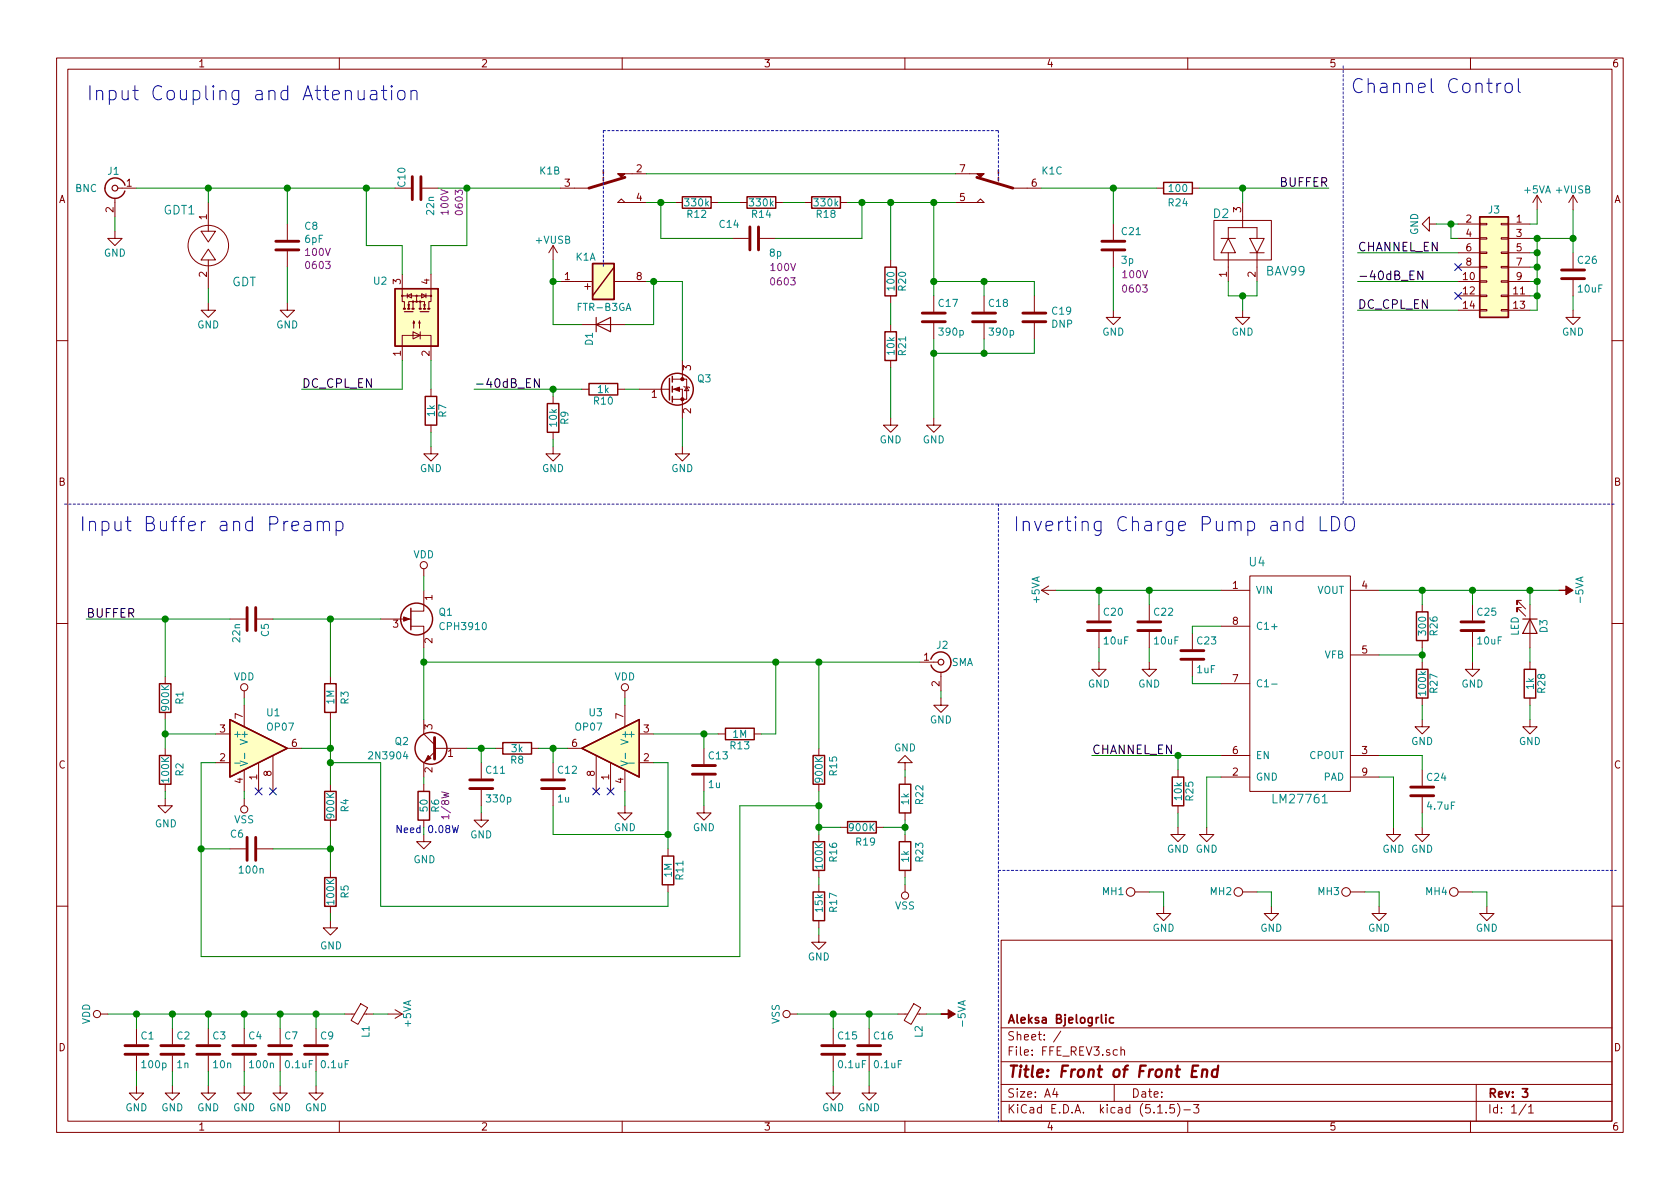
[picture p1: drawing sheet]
<svg xmlns="http://www.w3.org/2000/svg" width="297mm" height="210mm" viewBox="0 0 297 210" stroke-linecap="round" stroke-linejoin="round" font-family="sans-serif">
<defs><g id="words">
<g font-size="3.5" fill="#0000c2">
<text x="15.2" y="17.8">Input Coupling and Attenuation</text>
<text x="238.8" y="16.5">Channel Control</text>
<text x="14" y="94">Input Buffer and Preamp</text>
<text x="179.1" y="94">Inverting Charge Pump and LDO</text>
</g>
<text font-size="2.8" fill="#840000" x="178" y="190.5">Title: Front of Front End</text>
<g font-size="2.1">
<text x="226.3" y="33">BUFFER</text>
<text x="240" y="44.4">CHANNEL_EN</text>
<text x="240" y="49.5">-40dB_EN</text>
<text x="240" y="54.6">DC_CPL_EN</text>
<text x="53.3" y="68.6">DC_CPL_EN</text>
<text x="83.8" y="68.6">-40dB_EN</text>
<text x="15.2" y="109.2">BUFFER</text>
<text x="193" y="133.3">CHANNEL_EN</text>
</g>
<g font-size="2.1" fill="#008484">
<text x="28.9" y="37.9">GDT1</text>
<text x="214.6" y="38.6">D2</text>
<text x="40.9" y="50.6">GDT</text>
<text x="223.9" y="48.7">BAV99</text>
<text x="220.9" y="100.1">U4</text>
<text x="225.4" y="142.1">LM27761</text>
</g>
<g font-size="2.1" fill="#840000">
<text x="178" y="184">Sheet: /</text>
<text x="178" y="181">Aleksa Bjelogrlic</text>
<text x="178" y="186.7">File: FFE_REV3.sch</text>
<text x="178" y="196.9">KiCad E.D.A. kicad (5.1.5)-3</text>
<text x="178" y="194.1">Size: A4</text>
<text x="200" y="194.1">Date:</text>
<text x="263" y="194.1">Rev: 3</text>
<text x="263" y="196.9">Id: 1/1</text>
</g>
<g font-size="1.8" fill="#840000">
<text x="35" y="11.9">1</text>
<text x="85" y="11.9">2</text>
<text x="135" y="11.9">3</text>
<text x="185" y="11.9">4</text>
<text x="235" y="11.9">5</text>
<text x="285" y="11.9">6</text>
<text x="10.4" y="35.9">A</text>
<text x="22.4" y="33">1</text>
<text x="99.8" y="33">3</text>
<text x="112.5" y="30.5">2</text>
<text x="112.5" y="35.6">4</text>
<text x="169.7" y="35.6">5</text>
<text x="169.7" y="30.5">7</text>
<text x="182.4" y="33">6</text>
<text x="285.4" y="35.9">A</text>
<text x="20.1" y="37.6" transform="rotate(-90 20.1 37.6)">2</text>
<text x="36.6" y="38.8" transform="rotate(-90 36.6 38.8)">1</text>
<text x="219.5" y="37.6" transform="rotate(-90 219.5 37.6)">3</text>
<text x="259.2" y="39.4">2</text>
<text x="259.2" y="41.9">4</text>
<text x="268.1" y="39.4">1</text>
<text x="268.1" y="41.9">3</text>
<text x="259.2" y="44.4">6</text>
<text x="259.2" y="47">8</text>
<text x="268.1" y="44.4">5</text>
<text x="268.1" y="47">7</text>
<text x="36.6" y="49" transform="rotate(-90 36.6 49)">2</text>
<text x="70.9" y="50.3" transform="rotate(-90 70.9 50.3)">3</text>
<text x="75.9" y="50.3" transform="rotate(-90 75.9 50.3)">4</text>
<text x="99.8" y="49.5">1</text>
<text x="112.5" y="49.5">8</text>
<text x="216.9" y="49" transform="rotate(-90 216.9 49)">1</text>
<text x="222" y="49" transform="rotate(-90 222 49)">2</text>
<text x="258.7" y="49.5">10</text>
<text x="258.7" y="52.1">12</text>
<text x="267.6" y="52.1">11</text>
<text x="268.1" y="49.5">9</text>
<text x="258.7" y="54.6">14</text>
<text x="267.6" y="54.6">13</text>
<text x="70.9" y="63" transform="rotate(-90 70.9 63)">1</text>
<text x="75.9" y="63" transform="rotate(-90 75.9 63)">2</text>
<text x="122.2" y="65.5" transform="rotate(-90 122.2 65.5)">3</text>
<text x="115.2" y="70.4">1</text>
<text x="122.2" y="73.1" transform="rotate(-90 122.2 73.1)">2</text>
<text x="10.4" y="85.9">B</text>
<text x="285.4" y="85.9">B</text>
<text x="76.5" y="106.1" transform="rotate(-90 76.5 106.1)">1</text>
<text x="218" y="104.1">1</text>
<text x="240.8" y="104.1">4</text>
<text x="69.5" y="111">3</text>
<text x="76.5" y="113.8" transform="rotate(-90 76.5 113.8)">2</text>
<text x="218" y="110.5">8</text>
<text x="163.3" y="116.8">1</text>
<text x="240.8" y="115.6">5</text>
<text x="166.1" y="121.4" transform="rotate(-90 166.1 121.4)">2</text>
<text x="218" y="120.6">7</text>
<text x="38.9" y="129.5">3</text>
<text x="42.9" y="127.1" transform="rotate(-90 42.9 127.1)">7</text>
<text x="76.5" y="129" transform="rotate(-90 76.5 129)">3</text>
<text x="110.2" y="127.1" transform="rotate(-90 110.2 127.1)">7</text>
<text x="113.8" y="129.5">3</text>
<text x="10.4" y="135.9">C</text>
<text x="38.9" y="134.6">2</text>
<text x="45.5" y="137.9" transform="rotate(-90 45.5 137.9)">1</text>
<text x="48" y="137.3" transform="rotate(-90 48 137.3)">8</text>
<text x="51.6" y="132.1">6</text>
<text x="76.5" y="136.6" transform="rotate(-90 76.5 136.6)">2</text>
<text x="79.2" y="133.9">1</text>
<text x="101.1" y="132.1">6</text>
<text x="105.2" y="137.3" transform="rotate(-90 105.2 137.3)">8</text>
<text x="107.7" y="137.9" transform="rotate(-90 107.7 137.9)">1</text>
<text x="113.8" y="134.6">2</text>
<text x="218" y="137.2">2</text>
<text x="218" y="133.3">6</text>
<text x="240.8" y="133.3">3</text>
<text x="240.8" y="137.2">9</text>
<text x="285.4" y="135.9">C</text>
<text x="42.9" y="138.5" transform="rotate(-90 42.9 138.5)">4</text>
<text x="110.2" y="138.5" transform="rotate(-90 110.2 138.5)">4</text>
<text x="10.4" y="185.9">D</text>
<text x="285.4" y="185.9">D</text>
<text x="35" y="199.9">1</text>
<text x="85" y="199.9">2</text>
<text x="135" y="199.9">3</text>
<text x="185" y="199.9">4</text>
<text x="235" y="199.9">5</text>
<text x="285" y="199.9">6</text>
</g>
<g font-size="1.8" fill="#008484">
<text x="13.3" y="34">BNC</text>
<text x="19.1" y="30.9">J1</text>
<text x="71.7" y="33" transform="rotate(-90 71.7 33)">C10</text>
<text x="95.5" y="30.9">K1B</text>
<text x="184.3" y="30.9">K1C</text>
<text x="206.8" y="34">100</text>
<text x="269.5" y="34.2">+5VA +VUSB</text>
<text x="53.9" y="40.6">C8</text>
<text x="76.8" y="37.9" transform="rotate(-90 76.8 37.9)">22n</text>
<text x="121.2" y="36.5">330k</text>
<text x="121.6" y="38.5">R12</text>
<text x="127.3" y="40.3">C14</text>
<text x="132.7" y="36.5">330k</text>
<text x="133" y="38.5">R14</text>
<text x="144.1" y="36.5">330k</text>
<text x="144.4" y="38.5">R18</text>
<text x="198.4" y="41.6">C21</text>
<text x="206.7" y="36.5">R24</text>
<text x="250.7" y="41.6" transform="rotate(-90 250.7 41.6)">GND</text>
<text x="263.2" y="37.8">J3</text>
<text x="18.4" y="45.4">GND</text>
<text x="53.9" y="42.9">6pF</text>
<text x="94.8" y="43.1">+VUSB</text>
<text x="101.8" y="46.1">K1A</text>
<text x="136.1" y="45.4">8p</text>
<text x="198.3" y="46.7">3p</text>
<text x="279" y="46.7">C26</text>
<text x="66.1" y="50.3">U2</text>
<text x="158.2" y="51.2" transform="rotate(-90 158.2 51.2)">100</text>
<text x="160.2" y="51.4" transform="rotate(-90 160.2 51.4)">R20</text>
<text x="279.1" y="51.7">10uF</text>
<text x="34.9" y="58.1">GND</text>
<text x="48.8" y="58.1">GND</text>
<text x="102.3" y="55">FTR-B3GA</text>
<text x="166" y="54.3">C17</text>
<text x="166.2" y="59.4">390p</text>
<text x="174.9" y="54.3">C18</text>
<text x="175.1" y="59.4">390p</text>
<text x="186" y="58">DNP</text>
<text x="186.1" y="55.6">C19</text>
<text x="194.9" y="59.4">GND</text>
<text x="217.8" y="59.4">GND</text>
<text x="276.2" y="59.4">GND</text>
<text x="104.8" y="61.1" transform="rotate(-90 104.8 61.1)">D1</text>
<text x="158.2" y="62.7" transform="rotate(-90 158.2 62.7)">10k</text>
<text x="160.2" y="62.8" transform="rotate(-90 160.2 62.8)">R21</text>
<text x="105.1" y="71.5">R10</text>
<text x="105.7" y="69.5">1k</text>
<text x="123.4" y="67.6">Q3</text>
<text x="76.9" y="73.6" transform="rotate(-90 76.9 73.6)">1k</text>
<text x="78.9" y="73.8" transform="rotate(-90 78.9 73.8)">R7</text>
<text x="98.5" y="75.4" transform="rotate(-90 98.5 75.4)">10k</text>
<text x="100.5" y="75" transform="rotate(-90 100.5 75)">R9</text>
<text x="74.2" y="83.5">GND</text>
<text x="95.8" y="83.5">GND</text>
<text x="118.7" y="83.5">GND</text>
<text x="155.5" y="78.4">GND</text>
<text x="163.1" y="78.4">GND</text>
<text x="73.1" y="98.7">VDD</text>
<text x="183.8" y="106.6" transform="rotate(-90 183.8 106.6)">+5VA</text>
<text x="222" y="105">VIN</text>
<text x="232.8" y="105">VOUT</text>
<text x="280" y="106.4" transform="rotate(-90 280 106.4)">-5VA</text>
<text x="42.5" y="113.5" transform="rotate(-90 42.5 113.5)">22n</text>
<text x="47.5" y="112.5" transform="rotate(-90 47.5 112.5)">C5</text>
<text x="77.6" y="108.9">Q1</text>
<text x="78.1" y="111.4">CPH3910</text>
<text x="195.2" y="108.9">C20</text>
<text x="195.3" y="114">10uF</text>
<text x="204.1" y="108.9">C22</text>
<text x="204.2" y="114">10uF</text>
<text x="211.7" y="114">C23</text>
<text x="222" y="111.4">C1+</text>
<text x="252.1" y="112.2" transform="rotate(-90 252.1 112.2)">300</text>
<text x="254.2" y="112.3" transform="rotate(-90 254.2 112.3)">R26</text>
<text x="261.3" y="108.9">C25</text>
<text x="261.3" y="114">10uF</text>
<text x="268.5" y="112.5" transform="rotate(-90 268.5 112.5)">LED</text>
<text x="273.6" y="111.9" transform="rotate(-90 273.6 111.9)">D3</text>
<text x="165.7" y="114.7">J2</text>
<text x="168.2" y="117.8">SMA</text>
<text x="211.7" y="119">1uF</text>
<text x="234.2" y="116.5">VFB</text>
<text x="29.9" y="125.5" transform="rotate(-90 29.9 125.5)">900K</text>
<text x="32.4" y="124.5" transform="rotate(-90 32.4 124.5)">R1</text>
<text x="41.3" y="120.3">VDD</text>
<text x="59.1" y="124.5" transform="rotate(-90 59.1 124.5)">1M</text>
<text x="61.6" y="124.5" transform="rotate(-90 61.6 124.5)">R3</text>
<text x="108.6" y="120.3">VDD</text>
<text x="192.4" y="121.6">GND</text>
<text x="201.2" y="121.6">GND</text>
<text x="222" y="121.5">C1-</text>
<text x="252.1" y="122.8" transform="rotate(-90 252.1 122.8)">100k</text>
<text x="254.2" y="122.5" transform="rotate(-90 254.2 122.5)">R27</text>
<text x="258.4" y="121.6">GND</text>
<text x="271.2" y="121.9" transform="rotate(-90 271.2 121.9)">1k</text>
<text x="273.2" y="122.5" transform="rotate(-90 273.2 122.5)">R28</text>
<text x="41.1" y="130.4">+</text>
<text x="43.8" y="131.2" transform="rotate(-90 43.8 131.2)">V+</text>
<text x="47.2" y="126.7">U1</text>
<text x="47.3" y="129.2">OP07</text>
<text x="69.9" y="131.7">Q2</text>
<text x="101.8" y="129.2">OP07</text>
<text x="104.2" y="126.7">U3</text>
<text x="111.1" y="131.2" transform="rotate(-90 111.1 131.2)">V+</text>
<text x="111.5" y="130.4">+</text>
<text x="129.6" y="130.5">1M</text>
<text x="164.4" y="127.9">GND</text>
<text x="249.5" y="131.7">GND</text>
<text x="268.6" y="131.7">GND</text>
<text x="32.4" y="137.2" transform="rotate(-90 32.4 137.2)">R2</text>
<text x="65.5" y="134.3">2N3904</text>
<text x="86" y="136.8">C11</text>
<text x="90.3" y="135">R8</text>
<text x="90.5" y="133">3k</text>
<text x="98.7" y="136.8">C12</text>
<text x="125.4" y="134.3">C13</text>
<text x="129.2" y="132.5">R13</text>
<text x="148" y="137.1" transform="rotate(-90 148 137.1)">R15</text>
<text x="158.1" y="132.9">GND</text>
<text x="222" y="134.2">EN</text>
<text x="231.5" y="134.2">CPOUT</text>
<text x="29.9" y="138.2" transform="rotate(-90 29.9 138.2)">100K</text>
<text x="61.6" y="143.6" transform="rotate(-90 61.6 143.6)">R4</text>
<text x="75.6" y="143.4" transform="rotate(-90 75.6 143.4)">50</text>
<text x="77.6" y="143.6" transform="rotate(-90 77.6 143.6)">R6</text>
<text x="86.2" y="141.9">330p</text>
<text x="98.7" y="141.9">1u</text>
<text x="125.3" y="139.4">1u</text>
<text x="145.5" y="138.2" transform="rotate(-90 145.5 138.2)">900K</text>
<text x="160.7" y="142.3" transform="rotate(-90 160.7 142.3)">1k</text>
<text x="163.2" y="142.2" transform="rotate(-90 163.2 142.2)">R22</text>
<text x="209" y="141.4" transform="rotate(-90 209 141.4)">10k</text>
<text x="211" y="141.5" transform="rotate(-90 211 141.5)">R25</text>
<text x="222" y="138">GND</text>
<text x="234" y="138">PAD</text>
<text x="252.4" y="138.1">C24</text>
<text x="252.5" y="143.2">4.7uF</text>
<text x="27.4" y="146.3">GND</text>
<text x="40.8" y="148.1">C6</text>
<text x="41.4" y="145.6">VSS</text>
<text x="59.1" y="144.6" transform="rotate(-90 59.1 144.6)">900K</text>
<text x="83.1" y="148.3">GND</text>
<text x="108.5" y="147">GND</text>
<text x="122.5" y="147">GND</text>
<text x="150.3" y="147">900K</text>
<text x="151.4" y="149.5">R19</text>
<text x="42.4" y="154.5">100n</text>
<text x="73.1" y="152.6">GND</text>
<text x="118.8" y="155.1" transform="rotate(-90 118.8 155.1)">1M</text>
<text x="120.8" y="155.5" transform="rotate(-90 120.8 155.5)">R11</text>
<text x="145.5" y="153.5" transform="rotate(-90 145.5 153.5)">100K</text>
<text x="148" y="152.3" transform="rotate(-90 148 152.3)">R16</text>
<text x="160.7" y="152.4" transform="rotate(-90 160.7 152.4)">1k</text>
<text x="163.2" y="152.3" transform="rotate(-90 163.2 152.3)">R23</text>
<text x="206.3" y="150.8">GND GND</text>
<text x="244.4" y="150.8">GND GND</text>
<text x="59.1" y="159.8" transform="rotate(-90 59.1 159.8)">100K</text>
<text x="61.6" y="158.8" transform="rotate(-90 61.6 158.8)">R5</text>
<text x="145.5" y="161.2" transform="rotate(-90 145.5 161.2)">15k</text>
<text x="148" y="161.2" transform="rotate(-90 148 161.2)">R17</text>
<text x="158.3" y="160.8">VSS</text>
<text x="195" y="158.3">MH1</text>
<text x="214" y="158.3">MH2</text>
<text x="233.1" y="158.3">MH3</text>
<text x="252.1" y="158.3">MH4</text>
<text x="56.6" y="167.9">GND</text>
<text x="203.8" y="164.8">GND</text>
<text x="222.8" y="164.8">GND</text>
<text x="241.9" y="164.8">GND</text>
<text x="260.9" y="164.8">GND</text>
<text x="142.8" y="169.8">GND</text>
<text x="15.9" y="181.1" transform="rotate(-90 15.9 181.1)">VDD</text>
<text x="25" y="183.8">C1</text>
<text x="31.3" y="183.8">C2</text>
<text x="37.7" y="183.8">C3</text>
<text x="44" y="183.8">C4</text>
<text x="50.4" y="183.8">C7</text>
<text x="56.7" y="183.8">C9</text>
<text x="65.3" y="183.4" transform="rotate(-90 65.3 183.4)">L1</text>
<text x="72.7" y="181.6" transform="rotate(-90 72.7 181.6)">+5VA</text>
<text x="137.8" y="181.1" transform="rotate(-90 137.8 181.1)">VSS</text>
<text x="148.2" y="183.8">C15</text>
<text x="154.6" y="183.8">C16</text>
<text x="163.1" y="183.4" transform="rotate(-90 163.1 183.4)">L2</text>
<text x="170.7" y="181.3" transform="rotate(-90 170.7 181.3)">-5VA</text>
<text x="25.2" y="188.9">100p</text>
<text x="31.3" y="188.9">1n</text>
<text x="37.8" y="188.9">10n</text>
<text x="44.3" y="188.9">100n</text>
<text x="50.5" y="188.9">0.1uF</text>
<text x="56.9" y="188.9">0.1uF</text>
<text x="148.3" y="188.9">0.1uF</text>
<text x="154.7" y="188.9">0.1uF</text>
<text x="22.2" y="196.5">GND</text>
<text x="28.5" y="196.5">GND</text>
<text x="34.9" y="196.5">GND</text>
<text x="41.2" y="196.5">GND</text>
<text x="47.6" y="196.5">GND</text>
<text x="53.9" y="196.5">GND</text>
<text x="145.4" y="196.5">GND</text>
<text x="151.7" y="196.5">GND</text>
</g>
<g font-size="1.8" fill="#840084">
<text x="79.3" y="37.9" transform="rotate(-90 79.3 37.9)">100V</text>
<text x="81.8" y="37.8" transform="rotate(-90 81.8 37.8)">0603</text>
<text x="54.1" y="45.3">100V</text>
<text x="54.3" y="47.6">0603</text>
<text x="136.4" y="47.9">100V</text>
<text x="136.5" y="50.5">0603</text>
<text x="198.6" y="49.2">100V</text>
<text x="198.7" y="51.7">0603</text>
<text x="79.4" y="144.5" transform="rotate(-90 79.4 144.5)">1/8W</text>
</g>
<text font-size="1.8" fill="#0000c2" x="69.8" y="147.3">Need 0.08W</text>
</g></defs>
<g fill="none" stroke="#840000" stroke-width=".18">
<path d="M10 10.3h277v189.9h-277zM12 12.2h273v186.1h-273zM60 10.3v1.9M110 10.3v1.9M160 10.3v1.9M210 10.3v1.9M260 10.3v1.9M20.3 35v3.3M20.8 33.3h3.3M36.8 35.8v5.1M50.8 39.6v2.8M69.8 33.3h2.8"/>
<path d="M74.7 33.3h2.8M99.1 33.3h5M109.2 30.7h5.1M110.5 35.8l-.6-.6-.7 .6h5.1M119.4 35.8h1.2M125.7 35.8h1.3M130.8 35.8h1.3M137.2 35.8h1.2M142.2 35.8h1.3M148.6 35.8h1.3M168.9 35.8h5.1l-.6-.6-.7 .6M168.9 30.7h5.1"/>
<path d="M179.1 33.3h5M196.8 39.6v2.8M204.5 33.3h1.2M210.8 33.3h1.3M214.6 39h10.2v7h-10.2zM219.7 35.8v4.5M252.7 39.6v-1.3l-1.2 1.3 1.2 1.3v-1.3h1.3M257.8 39.6h3.8M261.6 39.5h1.3v.2h-1.3zM265.4 39.5h1.3v.2h-1.3zM266.7 39.6h3.8M271.8 34.5l-.8 1.3"/>
<path d="M271.8 34.5v2.6M271.8 34.5l.7 1.3M278.1 34.5v2.6M278.1 34.5l-.7 1.3M278.1 34.5l.8 1.3M20.3 40.9v1.3h1.3l-1.3 1.2-1.3-1.2h1.3M35.6 40.9h2.5l-1.3 1.9zM36.8 53.6v1.3h1.3l-1.3 1.2-1.2-1.2h1.2M36.8 44.1l1.3 1.9h-2.5zM36.8 46v5M50.8 53.6v1.3h1.3l-1.3 1.2-1.3-1.2h1.3M50.8 44.4v2.8"/>
<path d="M71.1 48.5v4.8h.4v1.2M71.1 52.3h5.1M72 52.3l.8-.4v.8zM72 51.9v.8M72.1 53.8h.3l-.1 .6zM73 53.3h-.7v1.2M73 58.7l1.3 .6-1.3 .6zM73 54.5v-1.2h1.3v1.2M73.2 56.8l-.2 .3h.3l-.1-.3v1.2M73.7 52.3v1M74.2 56.8l-.2 .3h.3l-.1-.3v1.2M74.3 59.3h-3.2v4.4"/>
<path d="M74.3 59.3h1.9v4.4M74.3 53.3h.8v1.2M74.3 58.7v1.2M74.5 51.9l.8 .4-.8 .4zM74.9 53.8h.3l-.1 .6zM75.3 51.9v.8M76.2 48.5v4.8h-.4v1.2M97.8 43.4l.8 1.3M97.8 43.4v2.6M97.8 43.4l-.8 1.3M99.1 49.8h5.7M102.9 57.4h7.6"/>
<path d="M103.4 50.7h1M103.9 50.2v1M108.6 49.8h5.7M129.5 42.2h2.8M134.4 42.2h2.8M157.5 46v1.2M157.5 52.3v1.3M157.5 57.4v1.3M165.1 52.3v2.8M165.1 57.1v2.8M174 52.3v2.8M174 57.1v2.8"/>
<path d="M182.9 52.3v2.8M182.9 57.1v2.8M196.8 54.9v1.2h1.3l-1.3 1.3-1.2-1.3h1.2M196.8 44.4v2.8M215.9 42.2h2.5M217.2 40.3v1.9zM217.2 40.3h5zM217.2 42.2l1.2 2.5h-2.5zM217.2 44.7v5.1M219.7 54.9v1.2h1.3l-1.3 1.3-1.3-1.3h1.3M221 42.2h2.5l-1.3 2.5zM221 44.7h2.5"/>
<path d="M222.2 40.3v1.9zM222.2 44.7v5.1M257.8 52.3h3.8M257.8 42.2h3.8M257.8 49.8h3.8M257.8 44.7h3.8M257.8 54.9h3.8M257.8 47.2h3.8M261.6 54.7h1.3v.3h-1.3zM261.6 52.2h1.3v.2h-1.3zM261.6 49.7h1.3v.2h-1.3zM261.6 47.1h1.3v.3h-1.3z"/>
<path d="M261.6 44.6h1.3v.2h-1.3zM261.6 42h1.3v.3h-1.3zM265.4 54.7h1.3v.3h-1.3zM265.4 52.2h1.3v.2h-1.3zM265.4 49.7h1.3v.2h-1.3zM265.4 47.1h1.3v.3h-1.3zM265.4 44.6h1.3v.2h-1.3zM265.4 42h1.3v.3h-1.3zM266.7 52.3h3.8M266.7 42.2h3.8M266.7 49.8h3.8M266.7 44.7h3.8"/>
<path d="M266.7 54.9h3.8M266.7 47.2h3.8M278.1 54.9v1.2h1.3l-1.3 1.3-1.2-1.3h1.2M278.1 44.7v2.8M278.1 49.5v2.8M10 60.2h2M76.2 79v1.3h1.3l-1.3 1.2-1.3-1.2h1.3M76.2 68.8v1.3M76.2 75.2v1.2M97.8 79v1.3h1.3l-1.3 1.2-1.3-1.2h1.3M97.8 70.1v1.3M97.8 76.4v1.3"/>
<path d="M102.9 68.8h1.2M109.2 68.8h1.3M113 68.8h5.4M118.9 68.8h1.7v5.1M118.9 67.1h1.7M120.6 79v1.3h1.3l-1.3 1.2-1.2-1.2h1.2M120.6 67.1h.8v3.5h-2.5M120.6 63.7v3.4M120.9 68.3l.1 .1h.8l.1 .2M121.4 68.4l.4 .7h-.8zM157.5 73.9v1.3h1.2l-1.2 1.2-1.3-1.2h1.3M157.5 63.7v1.3"/>
<path d="M165.1 73.9v1.3h1.3l-1.3 1.2-1.3-1.2h1.3M285 60.2h2M10 110.3h2M29.2 119.6v1.3M40.6 109.5h2.8M45.5 109.5h2.8M58.4 119.6v1.3M67.3 109.5h5.3M72.6 110.7h2.3v3.8M74.9 104.4v3.7h-2.3M74.9 100.6v1.2M162.6 117.1h3.3"/>
<path d="M166.4 118.9v3.3M184.1 104.4l1.3 .8M184.1 104.4h2.6M185.4 103.6l-1.3 .8M194.3 117.1v1.3h1.3l-1.3 1.2-1.3-1.2h1.3M194.3 106.9v2.8M194.3 111.8v2.7M203.2 117.1v1.3h1.3l-1.3 1.2-1.3-1.2h1.3M203.2 106.9v2.8M203.2 111.8v2.7M210.8 112v2.8M210.8 116.8v2.8"/>
<path d="M215.9 104.4h5.1M215.9 110.7h5.1M221 101.8h17.8v38.1h-17.8zM238.8 104.4h5M238.8 115.8h5M251.5 106.9v1.3M251.5 113.3v1.2M251.5 117.1v1.3M260.3 117.1v1.3h1.3l-1.3 1.2-1.2-1.2h1.2M260.3 106.9v2.8M260.3 111.8v2.7M269 106.2h-.8v.7v-.7l1.5 1.5"/>
<path d="M269 107.4h-.8v.8v-.8l1.5 1.6M270.5 106.9v7.6M270.5 117.1v1.3M285 110.3h2M29.2 126v1.2M29.2 132.3v1.3M29.2 138.7v1.2M38.1 129.8h2.5M38.1 134.9h2.5M43.2 122.2v1.2M43.2 124.7v3.8M43.2 136.1v3.8"/>
<path d="M45.7 134.9v5M48.3 133.6v6.3M50.8 132.3h2.5M58.4 126v1.2M58.4 138.7v1.2M74.9 127.2v2.6l1.9 1.9M74.9 138.7v1.2M76.8 133l-1.9 1.9v2.5M76.8 132.3h5.7M85.1 134.9v2.8M85.1 139.7v2.8M87.6 132.3h1.3"/>
<path d="M94 132.3h1.2M97.8 134.9v2.8M97.8 139.7v2.8M100.3 132.3h2.6M105.4 133.6v6.3M107.9 134.9v5M110.5 122.2v1.2M110.5 124.7v3.8M110.5 136.1v3.8M113 129.8h2.6M113 134.9h2.6M124.5 132.3v2.8"/>
<path d="M124.5 137.2v2.7M127 129.8h1.3M133.3 129.8h1.3M144.8 132.3v1.3M144.8 138.7v1.2M160 134.9h1.3l-1.3-1.3-1.3 1.3h1.3v1.2M160 137.4v1.3M166.4 123.4v1.3h1.2l-1.2 1.3-1.3-1.3h1.3M208.3 136.1v1.3M215.9 137.4h5.1M215.9 133.6h5.1M215.9 120.9h5.1"/>
<path d="M238.8 137.4h5M238.8 133.6h5M251.5 127.2v1.3h1.2l-1.2 1.3-1.3-1.3h1.3M251.5 123.4v1.3M251.5 136.1v2.8M270.5 127.2v1.3h1.3l-1.3 1.3-1.3-1.3h1.3M270.5 123.4v1.3M29.2 141.2v1.3h1.3l-1.3 1.3-1.3-1.3h1.3M40.6 150.1h2.8M43.2 141.2v1.3M45.5 150.1h2.8M58.4 145v1.3"/>
<path d="M58.4 153.9v1.3M74.9 147.6v1.2h1.3l-1.3 1.3-1.2-1.3h1.2M74.9 145v1.3M85.1 143.8v1.2h1.3l-1.3 1.3-1.3-1.3h1.3M110.5 142.5v1.3h1.3l-1.3 1.2-1.3-1.2h1.3M118.1 150.1v1.3M118.1 156.5v1.2M124.5 142.5v1.3h1.2l-1.2 1.2-1.3-1.2h1.3M144.8 147.6v1.2M144.8 153.9v1.3M144.8 156.5v1.2M148.6 146.3h1.3"/>
<path d="M154.9 146.3h1.3M160 143.8v1.2M160 147.6v1.2M160 153.9v1.3M160 156.5v1.2M200.7 157.7h2.5M208.3 146.3v1.3h1.2l-1.2 1.2-1.3-1.2h1.3M208.3 142.5v1.3M213.4 146.3v1.3h1.2l-1.2 1.2-1.3-1.2h1.3M219.7 157.7h2.5M238.8 157.7h2.5M246.4 146.3v1.3h-1.3l1.3 1.2 1.2-1.2h-1.2"/>
<path d="M251.5 146.3v1.3h1.2l-1.2 1.2-1.3-1.2h1.3M251.5 141v2.8M257.8 157.7h2.5M10 160.2h2M17.8 179.3h1.2M58.4 162.8v1.3h1.3l-1.3 1.2-1.3-1.2h1.3M58.4 160.3v1.2M61 179.3h1.7M63.8 177.5l1.2 .7-1.7 2.9-1.2-.7zM64.4 179.3h1.6M68.6 179.3h2.5M69.8 178.6l1.3 .7"/>
<path d="M71.1 179.3l-1.3 .8M139.7 179.3h1.3M144.8 165.3v1.3h1.2l-1.2 1.3-1.3-1.3h1.3M144.8 162.8v1.3M158.7 179.3h1.8M161.6 177.5l1.2 .7-1.7 2.9-1.2-.7zM162.2 179.3h1.6M177 166.3h108v32h-108zM205.7 160.3v1.2h1.3l-1.3 1.3-1.2-1.3h1.2M224.8 160.3v1.2h1.3l-1.3 1.3-1.3-1.3h1.3M243.8 160.3v1.2h1.3l-1.3 1.3-1.2-1.3h1.2M262.9 160.3v1.2h1.3l-1.3 1.3-1.3-1.3h1.3"/>
<path d="M285 160.2h2M24.1 192v1.3h1.3l-1.3 1.3-1.2-1.3h1.2M24.1 181.9v2.8M24.1 186.7v2.8M30.5 192v1.3h1.2l-1.2 1.3-1.3-1.3h1.3M30.5 181.9v2.8M30.5 186.7v2.8M36.8 192v1.3h1.3l-1.3 1.3-1.2-1.3h1.2M36.8 181.9v2.8M36.8 186.7v2.8M43.2 192v1.3h1.2l-1.2 1.3-1.3-1.3h1.3M43.2 181.9v2.8"/>
<path d="M43.2 186.7v2.8M49.5 192v1.3h1.3l-1.3 1.3-1.2-1.3h1.2M49.5 181.9v2.8M49.5 186.7v2.8M55.9 192v1.3h1.2l-1.2 1.3-1.3-1.3h1.3M55.9 181.9v2.8M55.9 186.7v2.8M60 198.3v1.9M110 198.3v1.9M147.3 192v1.3h1.3l-1.3 1.3-1.3-1.3h1.3M147.3 181.9v2.8M147.3 186.7v2.8"/>
<path d="M153.7 192v1.3h1.2l-1.2 1.3-1.3-1.3h1.3M153.7 181.9v2.8M153.7 186.7v2.8M160 198.3v1.9M177 194.8h108M177 191.8h108M177 187.8h108M177 181.8h108M186.5 192.5l-.4 1h1M186.8 193v1M187.6 182.3l-1.3 2M197 191.8v3"/>
<path d="M197.6 185.7l-.5-.1-.3 .3 .1 .6 .2 .1 .5-.1M198.2 185.7l.2-.1 .4 .1v.9M198.2 185.1v1.5M204.7 196.8h.8M206.2 196.7v.1M207.6 195.3h-.7l-.1 .7 .2-.1 .5 .1 .2 .2-.1 .5-.2 .1-.6-.1M208.2 195.1a1.71 1.71 0 0 1 0 2.3M209.3 196.3h1.2M210 198.3v1.9M211 195.3h1l-.5 .6 .4 .1v.7l-.2 .1-.7-.1M260 198.3v1.9M261 191.8v6.5"/>
<path d="M269.8 195.2l-1.2 2M270.3 195.8l.4-.5v1.5M270.3 196.8h.8"/>
<circle cx="36.8" cy="43.4" r="3.6"/>
<circle cx="71.1" cy="52.3" r=".13"/>
<circle cx="73" cy="53.3" r=".13"/>
<circle cx="73.7" cy="53.3" r=".13"/>
<circle cx="73.7" cy="52.3" r=".13"/>
<circle cx="74.3" cy="53.3" r=".13"/>
<circle cx="76.2" cy="52.3" r=".13"/>
<circle cx="74.9" cy="99.9" r=".63"/>
<circle cx="43.2" cy="121.5" r=".63"/>
<circle cx="110.5" cy="121.5" r=".63"/>
<circle cx="43.2" cy="143.1" r=".63"/>
<circle cx="160" cy="158.4" r=".63"/>
<circle cx="199.9" cy="157.7" r=".76"/>
<circle cx="218.9" cy="157.7" r=".76"/>
<circle cx="238" cy="157.7" r=".76"/>
<circle cx="257" cy="157.7" r=".76"/>
<circle cx="17.1" cy="179.3" r=".63"/>
<circle cx="139.1" cy="179.3" r=".63"/>
</g>
<path d="M195.5 179.4v.2M195.5 179.9v1M196.9 180l-.4-.1-.3 .3v.6l.3 .1 .4-.1M269.2 192.5h.9l-.5 .6 .4 .1v.7l-.2 .1-.6-.1" fill="none" stroke="#840000" stroke-width=".3"/>
<path d="M210.8 189.4h.7M211.9 188.4h-1l-.2 2h.9M212.6 189.3a.5 .5 0 0 1 .9 .1l-.2 1M212.6 189.1l-.1 1.3M215.3 189.2a.73 .73 0 0 0-.9 .1l-.2 .8 .1 .2 .3 .1 .6-.1M215.4 188.4l-.3 2" fill="none" stroke="#840000" stroke-width=".41"/>
<g fill="none" stroke="#840000" stroke-width=".51">
<path d="M72.9 31.2v4.1M74.4 31.2v4.1M110.5 31.4l-6.4 1.9M172.7 31.4l6.4 1.9M48.8 44.2h4M48.8 42.7h4M132.6 40.1v4.1M134.1 40.1v4.1M163.1 56.9h4M163.1 55.4h4M172 56.9h4M172 55.4h4"/>
<path d="M180.8 56.9h4.1M180.8 55.4h4.1M194.8 44.2h4.1M194.8 42.7h4.1M276.1 49.3h4.1M276.1 47.7h4.1M43.7 107.4v4.1M45.2 107.4v4.1M192.3 111.5h4M192.3 110h4M201.2 111.5h4M201.2 110h4"/>
<path d="M208.8 116.6h4.1M208.8 115.1h4.1M258.3 111.5h4.1M258.3 110h4.1M76.8 130.4v3.8M83.1 139.4h4M83.1 137.9h4M95.8 139.4h4M95.8 137.9h4M122.4 136.9h4.1M122.4 135.4h4.1M249.4 139.2h4.1"/>
<path d="M43.7 148.1v4M45.2 148.1v4M249.4 140.7h4.1M22.1 186.4h4.1M22.1 184.9h4.1M28.4 186.4h4.1M28.4 184.9h4.1M34.8 186.4h4.1M34.8 184.9h4.1M41.1 186.4h4.1M41.1 184.9h4.1M47.5 186.4h4.1"/>
<path d="M47.5 184.9h4.1M53.8 186.4h4.1M53.8 184.9h4.1M145.3 186.4h4.1M145.3 184.9h4.1M151.6 186.4h4.1M151.6 184.9h4.1"/>
</g>
<g fill="none" stroke="#840000" stroke-width=".2">
<path d="M71.5 55.1h1.5M74.3 55.1h1.5M105.4 57.4l2.5-1.3v2.6zM105.4 56.1v2.6M269.2 109.5h2.6M270.5 109.5l1.3 2.5h-2.6z"/>
<circle cx="20.3" cy="33.3" r=".51"/>
<circle cx="166.4" cy="117.1" r=".51"/>
</g>
<g fill="none" stroke="#840000" stroke-width=".25">
<path d="M18.5 33.3a1.8 1.8 0 0 0 1.6 1.8 1.8 1.8 0 0 0 2-1.3M22.1 32.8a1.8 1.8 0 0 0-2-1.3 1.8 1.8 0 0 0-1.5 1.8M106.7 30.1v.6M106.7 31.4v.6M120.6 34.8h5.1v2h-5.1zM132.1 34.8h5.1v2h-5.1zM143.5 34.8h5.1v2h-5.1zM176.5 30.1v.6M176.5 31.4v.6M205.7 32.3h5.1v2h-5.1zM261.6 38.3h5.1v17.8h-5.1zM69.8 51h7.7v10.2h-7.7z"/>
<path d="M104.8 46.6h3.8v6.4h-3.8zM108.6 47.2l-3.8 5.1M156.5 58.7h2v5h-2zM156.5 47.2h2v5.1h-2zM75.2 70.1h2v5.1h-2zM96.8 71.4h2v5h-2zM104.1 67.8h5.1v2h-5.1zM118.4 66.9v3.8M118.9 66.5v1.1M118.9 68.3v1M118.9 70.1v1M72.6 107.6v3.8"/>
<path d="M164.6 116.6a1.8 1.8 0 0 1 2-1.3 1.8 1.8 0 0 1 1.5 1.8M168.1 117.1a1.8 1.8 0 0 1-1.5 1.8 1.8 1.8 0 0 1-2-1.3M250.4 108.2h2.1v5.1h-2.1zM250.4 118.4h2.1v5h-2.1zM269.5 118.4h2v5h-2zM28.2 133.6h2v5.1h-2zM28.2 120.9h2v5.1h-2zM40.6 127.2l10.2 5.1-10.2 5.1zM57.4 139.9h2v5.1h-2zM57.4 120.9h2v5.1h-2zM73.9 139.9h2v5.1h-2zM88.9 131.3h5.1v2h-5.1z"/>
<path d="M102.9 132.3l10.1-5.1v10.2zM128.3 128.8h5v2h-5zM143.8 133.6h2v5.1h-2zM159 138.7h2v5.1h-2zM207.3 137.4h2v5.1h-2zM57.4 155.2h2v5.1h-2zM117.1 151.4h2v5.1h-2zM143.8 157.7h2v5.1h-2zM143.8 148.8h2v5.1h-2zM149.9 145.3h5v2h-5zM159 148.8h2v5.1h-2z"/>
<circle cx="119.8" cy="68.8" r="2.82"/>
<circle cx="73.7" cy="109.5" r="2.82"/>
<circle cx="76.2" cy="132.3" r="2.82"/>
</g>
<g fill="#ffffc2" stroke="#ffffc2" stroke-width=".18">
<path d="M69.8 51h7.7v10.2h-7.7z"/>
<path d="M104.8 46.6h3.8v6.4h-3.8z"/>
<path d="M40.6 127.2l10.2 5.1-10.2 5.1z"/>
<path d="M102.9 132.3l10.1-5.1v10.2z"/>
<path d="M261.6 38.3h5.1v17.8h-5.1z"/>
</g>
<path d="M71.4 54.6h.2M72.1 54.6h.3M72.9 54.6h.3M74.2 54.6h.2M74.9 54.6h.3M75.7 54.6h.2" fill="none" stroke="#840000" stroke-width=".36"/>
<g fill="#840000" stroke="#840000" stroke-width=".18">
<path d="M172.7 30.7h1.3l-.6 .7z"/>
<path d="M109.2 30.7h1.3l-.6 .7z"/>
<path d="M275.6 104.4h1.3v-.8l1.2 .8-1.2 .8v-.8z"/>
<path d="M71.4 109.1l1 .4-1 .3z"/>
<path d="M119.1 68.8l1-.4v.8z"/>
<path d="M75.7 133.6l.5 .5-1 .5z"/>
<path d="M166.4 179.3h1.2v-.7l1.3 .7-1.3 .8v-.8z"/>
<circle cx="120.6" cy="70.6" r=".28"/>
<circle cx="120.6" cy="67.1" r=".28"/>
</g>
<path d="M41.5 134.9h1M42.5 134.6l1.2 .4-1.2 .4M43.3 133.2v1M109.8 134.6l1.2 .4-1.2 .4M110.6 133.2v1M111.2 134.9h.9M224.8 121h1M233.8 142h.9" fill="none" stroke="#008484" stroke-width=".18"/>
<path d="M237.5 11.7v77.4M106.7 23.1h69.8M106.7 23.1v24.1M176.5 23.1v8.9M11.4 89.1h274.3M176.5 89.1v109.3M176.5 153.9h109.2" fill="none" stroke="#0000c2" stroke-width=".18" stroke-dasharray=".4 .4"/>
<g fill="none" stroke="#008400" stroke-width=".18">
<path d="M20.3 38.3v2.6M24.1 33.3h45.7M36.8 33.3v2.5M50.8 33.3v6.3M64.8 33.3v10.1h6.3v5.1M77.5 33.3h21.6M82.5 33.3v10.1h-6.3v5.1M114.3 35.8h5.1M114.3 30.7h54.6M116.8 35.8v6.4h12.7M127 35.8h3.8M138.4 35.8h3.8"/>
<path d="M149.9 35.8h19M152.4 35.8v6.4h-15.2M157.5 35.8v10.2M165.1 35.8v16.5M184.1 33.3h20.4M196.8 33.3v6.3M212.1 33.3h22.8M219.7 33.3v2.5M254 39.6h3.8M256.5 39.6v2.6h1.3M271.8 37.1v2.5h-1.3M278.1 37.1v7.6"/>
<path d="M36.8 51v2.6M50.8 47.2v6.4M97.8 46v11.4h5.1M97.8 49.8h1.3M114.3 49.8h6.3v13.9M115.6 49.8v7.6h-5.1M157.5 53.6v3.8M165.1 49.8h17.8v2.5M165.1 59.9v14M174 49.8v2.5M174 59.9v2.6M182.9 59.9v2.6h-17.8"/>
<path d="M196.8 47.2v7.7M217.2 49.8v2.5h5v-2.5M219.7 52.3v2.6M240 44.7h17.8M240 54.9h17.8M240 49.8h17.8M270.5 42.2h7.6M270.5 44.7h1.3M270.5 47.2h1.3M270.5 49.8h1.3M270.5 52.3h1.3M271.8 42.2v12.7h-1.3"/>
<path d="M278.1 52.3v2.6M71.1 63.7v5.1h-17.8M76.2 63.7v5.1M76.2 76.4v2.6M83.8 68.8h19.1M97.8 68.8v1.3M97.8 77.7v1.3M110.5 68.8h2.5M120.6 73.9v5.1M157.5 65v8.9M15.2 109.5h25.4M29.2 109.5v10.1"/>
<path d="M48.3 109.5h19M58.4 109.5v10.1M74.9 101.8v2.6M74.9 114.5v12.7M74.9 117.1h87.7M137.2 117.1v12.7h-2.6M144.8 117.1v15.2M186.7 104.4h29.2M194.3 104.4v2.5M194.3 114.5v2.6M203.2 104.4v2.5M203.2 114.5v2.6"/>
<path d="M210.8 119.6v1.3h5.1M215.9 110.7h-5.1v1.3M243.8 104.4h31.8M243.8 115.8h7.7M251.5 104.4v2.5M251.5 114.5v2.6M260.3 104.4v2.5M260.3 114.5v2.6M270.5 104.4v2.5M270.5 114.5v2.6M29.2 129.8h8.9M29.2 127.2v5.1"/>
<path d="M29.2 139.9v1.3M38.1 134.9h-2.5v34.3h95.2v-26.7h14M43.2 123.4v1.3M43.2 139.9v1.3M53.3 132.3h5.1M58.4 134.9h8.9v25.4h50.8v-2.6M58.4 127.2v11.5M74.9 137.4v1.3M82.5 132.3h5.1M85.1 132.3v2.6M95.2 132.3h5.1M97.8 132.3v2.6"/>
<path d="M110.5 123.4v1.3M110.5 139.9v2.6M115.6 129.8h11.4M115.6 134.9h2.5v15.2M124.5 129.8v2.5M124.5 139.9v2.6M144.8 139.9v7.7M160 136.1v1.3M166.4 122.2v1.2M193 133.6h22.9M208.3 133.6v2.5M215.9 137.4h-2.5v8.9"/>
<path d="M243.8 133.6h7.7v2.5M243.8 137.4h2.6v8.9M251.5 124.7v2.5M270.5 124.7v2.5M35.6 150.1h5M48.3 150.1h10.1M58.4 146.3v7.6M85.1 142.5v1.3M97.8 142.5v5.1h20.3M144.8 146.3h3.8M144.8 155.2v1.3M156.2 146.3h3.8"/>
<path d="M160 145v2.6M160 155.2v1.3M203.2 157.7h2.5v2.6M208.3 143.8v2.5M222.2 157.7h2.6v2.6M241.3 157.7h2.5v2.6M251.5 143.8v2.5M260.3 157.7h2.6v2.6M19 179.3h42M24.1 179.3v2.6M30.5 179.3v2.6M36.8 179.3v2.6"/>
<path d="M43.2 179.3v2.6M49.5 179.3v2.6M55.9 179.3v2.6M58.4 161.5v1.3M66 179.3h2.6M141 179.3h17.7M144.8 164.1v1.2M147.3 179.3v2.6M153.7 179.3v2.6M163.8 179.3h2.6M24.1 189.5v2.5M30.5 189.5v2.5"/>
<path d="M36.8 189.5v2.5M43.2 189.5v2.5M49.5 189.5v2.5M55.9 189.5v2.5M147.3 189.5v2.5M153.7 189.5v2.5"/>
</g>
<path d="M251.6 47.9v1.5l-.9-1.5v1.5M95.4 67v1.5l-.9-1.5v1.5" fill="none" stroke="#000" stroke-width=".18"/>
<g fill="none" stroke="#0000c2" stroke-width=".18">
<path d="M63.3 16l.1 1.5a.69 .69 0 0 0 1-.1M64.4 16v1.6M65.6 16.1l.2-.1 .7 .1 .1 1.5M66.6 16.6l-.2 .1h-.6a.48 .48 0 0 0-.4 .5 .48 .48 0 0 0 .4 .4h.6l.2-.1M67.5 16h.9M67.8 15.2v2.1l.1 .2 .5 .1M69.2 15.2l-.1 .1 .1 .1 .2-.1-.2-.1v.2M69.2 16v1.6M70.5 16.1a.69 .69 0 0 1 1.1 .4v.7a.67 .67 0 0 1-.6 .5 .67 .67 0 0 1-.7-.5v-.7zM72.7 16.2a.62 .62 0 0 1 1 .2v1.2M72.7 16v1.6M265.4 14.7a.59 .59 0 0 0-.7 .5"/>
<path d="M266.3 14.8a.69 .69 0 0 1 1.1 .4v.7a.67 .67 0 0 1-.7 .5 .67 .67 0 0 1-.6-.5v-.7zM268.5 13.9v2.1l.3 .4M53.9 92.3l.2-.1 .7 .1 .1 .3v1.2M54.9 92.8l-.8 .1a.48 .48 0 0 0-.4 .5 .48 .48 0 0 0 .4 .4l.8-.1M56.1 92.4a.62 .62 0 0 1 1.1 .2v1.2M56.1 92.2v1.6M57.2 92.6a.61 .61 0 0 1 .9-.3l.1 1.5M59.4 92.3a.82 .82 0 0 1 1.1 .1l.1 .3v.7l-.1 .2-.4 .2-.7-.1M59.4 92.2v2.5M233.4 91.4v2.4h1.2M235.4 91.4h.6a1.35 1.35 0 0 1 .9 1.2 1.35 1.35 0 0 1-.9 1.2h-.6zM237.9 91.7a.85 .85 0 0 1 1.4 0 1.9 1.9 0 0 1-.2 2 .84 .84 0 0 1-1.2-.2l-.1-.5z"/>
<path d="M80 146l.3 1.2 .2-.9 .2 .9 .4-1.2"/>
</g>
<g fill="#008400" stroke="#008400" stroke-width=".25">
<circle cx="144.8" cy="142.5" r=".51"/>
<circle cx="64.8" cy="33.3" r=".51"/>
<circle cx="58.4" cy="134.9" r=".51"/>
<circle cx="137.2" cy="117.1" r=".51"/>
<circle cx="35.6" cy="150.1" r=".51"/>
<circle cx="144.8" cy="117.1" r=".51"/>
<circle cx="97.8" cy="132.3" r=".51"/>
<circle cx="208.3" cy="133.6" r=".51"/>
<circle cx="144.8" cy="146.3" r=".51"/>
<circle cx="97.8" cy="68.8" r=".51"/>
<circle cx="160" cy="146.3" r=".51"/>
<circle cx="165.1" cy="35.8" r=".51"/>
<circle cx="147.3" cy="179.3" r=".51"/>
<circle cx="165.1" cy="49.8" r=".51"/>
<circle cx="203.2" cy="104.4" r=".51"/>
<circle cx="118.1" cy="147.6" r=".51"/>
<circle cx="58.4" cy="150.1" r=".51"/>
<circle cx="271.8" cy="42.2" r=".51"/>
<circle cx="36.8" cy="33.3" r=".51"/>
<circle cx="124.5" cy="129.8" r=".51"/>
<circle cx="271.8" cy="44.7" r=".51"/>
<circle cx="58.4" cy="132.3" r=".51"/>
<circle cx="58.4" cy="109.5" r=".51"/>
<circle cx="271.8" cy="47.2" r=".51"/>
<circle cx="29.2" cy="129.8" r=".51"/>
<circle cx="29.2" cy="109.5" r=".51"/>
<circle cx="271.8" cy="49.8" r=".51"/>
<circle cx="74.9" cy="117.1" r=".51"/>
<circle cx="271.8" cy="52.3" r=".51"/>
<circle cx="270.5" cy="104.4" r=".51"/>
<circle cx="30.5" cy="179.3" r=".51"/>
<circle cx="43.2" cy="179.3" r=".51"/>
<circle cx="251.5" cy="104.4" r=".51"/>
<circle cx="36.8" cy="179.3" r=".51"/>
<circle cx="260.3" cy="104.4" r=".51"/>
<circle cx="251.5" cy="115.8" r=".51"/>
<circle cx="49.5" cy="179.3" r=".51"/>
<circle cx="55.9" cy="179.3" r=".51"/>
<circle cx="115.6" cy="49.8" r=".51"/>
<circle cx="174" cy="62.5" r=".51"/>
<circle cx="278.1" cy="42.2" r=".51"/>
<circle cx="174" cy="49.8" r=".51"/>
<circle cx="256.5" cy="39.6" r=".51"/>
<circle cx="194.3" cy="104.4" r=".51"/>
<circle cx="97.8" cy="49.8" r=".51"/>
<circle cx="24.1" cy="179.3" r=".51"/>
<circle cx="152.4" cy="35.8" r=".51"/>
<circle cx="153.7" cy="179.3" r=".51"/>
<circle cx="116.8" cy="35.8" r=".51"/>
<circle cx="85.1" cy="132.3" r=".51"/>
<circle cx="219.7" cy="52.3" r=".51"/>
<circle cx="50.8" cy="33.3" r=".51"/>
<circle cx="82.6" cy="33.3" r=".51"/>
<circle cx="219.7" cy="33.3" r=".51"/>
<circle cx="157.5" cy="35.8" r=".51"/>
<circle cx="165.1" cy="62.5" r=".51"/>
<circle cx="196.9" cy="33.3" r=".51"/>
</g>
<path d="M257.2 51.7l1.2 1.2M257.2 46.6l1.2 1.2M258.4 51.7l-1.2 1.2M258.4 46.6l-1.2 1.2M45.1 139.3l1.2 1.3M46.3 139.3l-1.2 1.3M47.7 139.3l1.2 1.3M48.9 139.3l-1.2 1.3M104.8 139.3l1.2 1.3M106 139.3l-1.2 1.3M107.3 139.3l1.3 1.3M108.6 139.3l-1.3 1.3" fill="none" stroke="#000084" stroke-width=".18"/>
<use href="#words"/>
</svg>
